VERSION 5.7 ;
  NOWIREEXTENSIONATPIN ON ;
  DIVIDERCHAR "/" ;
  BUSBITCHARS "[]" ;
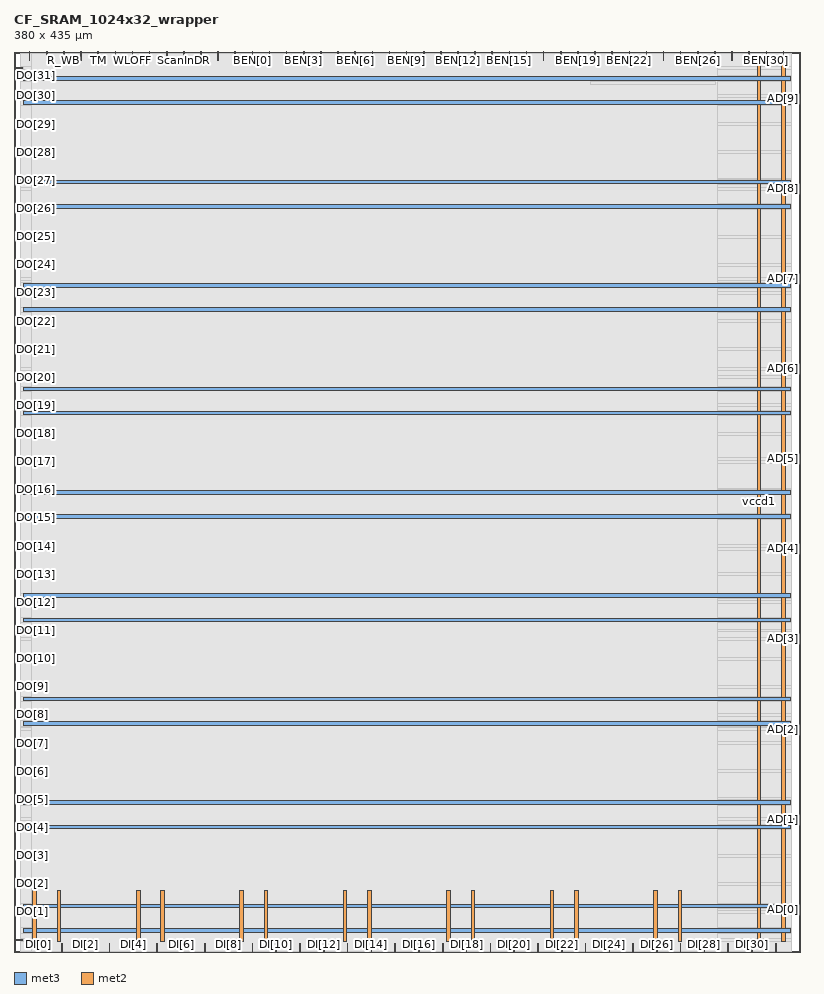
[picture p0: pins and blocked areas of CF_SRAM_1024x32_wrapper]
MACRO CF_SRAM_1024x32_wrapper
  CLASS BLOCK ;
  FOREIGN CF_SRAM_1024x32_wrapper ;
  ORIGIN 0.000 0.000 ;
  SIZE 380.000 BY 435.000 ;
  PIN AD[0]
    DIRECTION INPUT ;
    USE SIGNAL ;
    ANTENNAGATEAREA 0.247500 ;
    PORT
      LAYER met3 ;
        RECT 376.000 20.440 380.000 21.040 ;
    END
  END AD[0]
  PIN AD[1]
    DIRECTION INPUT ;
    USE SIGNAL ;
    ANTENNAGATEAREA 0.213000 ;
    PORT
      LAYER met3 ;
        RECT 376.000 63.960 380.000 64.560 ;
    END
  END AD[1]
  PIN AD[2]
    DIRECTION INPUT ;
    USE SIGNAL ;
    ANTENNAGATEAREA 0.213000 ;
    PORT
      LAYER met3 ;
        RECT 376.000 107.480 380.000 108.080 ;
    END
  END AD[2]
  PIN AD[3]
    DIRECTION INPUT ;
    USE SIGNAL ;
    ANTENNAGATEAREA 0.213000 ;
    PORT
      LAYER met3 ;
        RECT 376.000 151.000 380.000 151.600 ;
    END
  END AD[3]
  PIN AD[4]
    DIRECTION INPUT ;
    USE SIGNAL ;
    ANTENNAGATEAREA 0.159000 ;
    PORT
      LAYER met3 ;
        RECT 376.000 194.520 380.000 195.120 ;
    END
  END AD[4]
  PIN AD[5]
    DIRECTION INPUT ;
    USE SIGNAL ;
    ANTENNAGATEAREA 0.159000 ;
    PORT
      LAYER met3 ;
        RECT 376.000 238.040 380.000 238.640 ;
    END
  END AD[5]
  PIN AD[6]
    DIRECTION INPUT ;
    USE SIGNAL ;
    ANTENNAGATEAREA 0.213000 ;
    PORT
      LAYER met3 ;
        RECT 376.000 281.560 380.000 282.160 ;
    END
  END AD[6]
  PIN AD[7]
    DIRECTION INPUT ;
    USE SIGNAL ;
    ANTENNAGATEAREA 0.213000 ;
    PORT
      LAYER met3 ;
        RECT 376.000 325.080 380.000 325.680 ;
    END
  END AD[7]
  PIN AD[8]
    DIRECTION INPUT ;
    USE SIGNAL ;
    ANTENNAGATEAREA 0.213000 ;
    PORT
      LAYER met3 ;
        RECT 376.000 368.600 380.000 369.200 ;
    END
  END AD[8]
  PIN AD[9]
    DIRECTION INPUT ;
    USE SIGNAL ;
    ANTENNAGATEAREA 0.213000 ;
    PORT
      LAYER met3 ;
        RECT 376.000 412.120 380.000 412.720 ;
    END
  END AD[9]
  PIN BEN[0]
    DIRECTION INPUT ;
    USE SIGNAL ;
    ANTENNAGATEAREA 0.247500 ;
    ANTENNADIFFAREA 0.434700 ;
    PORT
      LAYER met2 ;
        RECT 115.090 431.000 115.370 435.000 ;
    END
  END BEN[0]
  PIN BEN[10]
    DIRECTION INPUT ;
    USE SIGNAL ;
    ANTENNAGATEAREA 0.247500 ;
    ANTENNADIFFAREA 0.434700 ;
    PORT
      LAYER met2 ;
        RECT 197.890 431.000 198.170 435.000 ;
    END
  END BEN[10]
  PIN BEN[11]
    DIRECTION INPUT ;
    USE SIGNAL ;
    ANTENNAGATEAREA 0.247500 ;
    ANTENNADIFFAREA 0.434700 ;
    PORT
      LAYER met2 ;
        RECT 206.170 431.000 206.450 435.000 ;
    END
  END BEN[11]
  PIN BEN[12]
    DIRECTION INPUT ;
    USE SIGNAL ;
    ANTENNAGATEAREA 0.247500 ;
    ANTENNADIFFAREA 0.434700 ;
    PORT
      LAYER met2 ;
        RECT 214.450 431.000 214.730 435.000 ;
    END
  END BEN[12]
  PIN BEN[13]
    DIRECTION INPUT ;
    USE SIGNAL ;
    ANTENNAGATEAREA 0.247500 ;
    ANTENNADIFFAREA 0.434700 ;
    PORT
      LAYER met2 ;
        RECT 222.730 431.000 223.010 435.000 ;
    END
  END BEN[13]
  PIN BEN[14]
    DIRECTION INPUT ;
    USE SIGNAL ;
    ANTENNAGATEAREA 0.247500 ;
    ANTENNADIFFAREA 0.434700 ;
    PORT
      LAYER met2 ;
        RECT 231.010 431.000 231.290 435.000 ;
    END
  END BEN[14]
  PIN BEN[15]
    DIRECTION INPUT ;
    USE SIGNAL ;
    ANTENNAGATEAREA 0.247500 ;
    ANTENNADIFFAREA 0.434700 ;
    PORT
      LAYER met2 ;
        RECT 239.290 431.000 239.570 435.000 ;
    END
  END BEN[15]
  PIN BEN[16]
    DIRECTION INPUT ;
    USE SIGNAL ;
    ANTENNAGATEAREA 0.213000 ;
    ANTENNADIFFAREA 0.434700 ;
    PORT
      LAYER met2 ;
        RECT 247.570 431.000 247.850 435.000 ;
    END
  END BEN[16]
  PIN BEN[17]
    DIRECTION INPUT ;
    USE SIGNAL ;
    ANTENNAGATEAREA 0.213000 ;
    ANTENNADIFFAREA 0.434700 ;
    PORT
      LAYER met2 ;
        RECT 255.850 431.000 256.130 435.000 ;
    END
  END BEN[17]
  PIN BEN[18]
    DIRECTION INPUT ;
    USE SIGNAL ;
    ANTENNAGATEAREA 0.159000 ;
    ANTENNADIFFAREA 0.434700 ;
    PORT
      LAYER met2 ;
        RECT 264.130 431.000 264.410 435.000 ;
    END
  END BEN[18]
  PIN BEN[19]
    DIRECTION INPUT ;
    USE SIGNAL ;
    ANTENNAGATEAREA 0.159000 ;
    ANTENNADIFFAREA 0.434700 ;
    PORT
      LAYER met2 ;
        RECT 272.410 431.000 272.690 435.000 ;
    END
  END BEN[19]
  PIN BEN[1]
    DIRECTION INPUT ;
    USE SIGNAL ;
    ANTENNAGATEAREA 0.247500 ;
    ANTENNADIFFAREA 0.434700 ;
    PORT
      LAYER met2 ;
        RECT 123.370 431.000 123.650 435.000 ;
    END
  END BEN[1]
  PIN BEN[20]
    DIRECTION INPUT ;
    USE SIGNAL ;
    ANTENNAGATEAREA 0.159000 ;
    ANTENNADIFFAREA 0.434700 ;
    PORT
      LAYER met2 ;
        RECT 280.690 431.000 280.970 435.000 ;
    END
  END BEN[20]
  PIN BEN[21]
    DIRECTION INPUT ;
    USE SIGNAL ;
    ANTENNAGATEAREA 0.159000 ;
    ANTENNADIFFAREA 0.434700 ;
    PORT
      LAYER met2 ;
        RECT 288.970 431.000 289.250 435.000 ;
    END
  END BEN[21]
  PIN BEN[22]
    DIRECTION INPUT ;
    USE SIGNAL ;
    ANTENNAGATEAREA 0.159000 ;
    ANTENNADIFFAREA 0.434700 ;
    PORT
      LAYER met2 ;
        RECT 297.250 431.000 297.530 435.000 ;
    END
  END BEN[22]
  PIN BEN[23]
    DIRECTION INPUT ;
    USE SIGNAL ;
    ANTENNAGATEAREA 0.159000 ;
    PORT
      LAYER met2 ;
        RECT 305.530 431.000 305.810 435.000 ;
    END
  END BEN[23]
  PIN BEN[24]
    DIRECTION INPUT ;
    USE SIGNAL ;
    ANTENNAGATEAREA 0.159000 ;
    PORT
      LAYER met2 ;
        RECT 313.810 431.000 314.090 435.000 ;
    END
  END BEN[24]
  PIN BEN[25]
    DIRECTION INPUT ;
    USE SIGNAL ;
    ANTENNAGATEAREA 0.159000 ;
    PORT
      LAYER met2 ;
        RECT 322.090 431.000 322.370 435.000 ;
    END
  END BEN[25]
  PIN BEN[26]
    DIRECTION INPUT ;
    USE SIGNAL ;
    ANTENNAGATEAREA 0.159000 ;
    PORT
      LAYER met2 ;
        RECT 330.370 431.000 330.650 435.000 ;
    END
  END BEN[26]
  PIN BEN[27]
    DIRECTION INPUT ;
    USE SIGNAL ;
    ANTENNAGATEAREA 0.159000 ;
    PORT
      LAYER met2 ;
        RECT 338.650 431.000 338.930 435.000 ;
    END
  END BEN[27]
  PIN BEN[28]
    DIRECTION INPUT ;
    USE SIGNAL ;
    ANTENNAGATEAREA 0.159000 ;
    PORT
      LAYER met2 ;
        RECT 346.930 431.000 347.210 435.000 ;
    END
  END BEN[28]
  PIN BEN[29]
    DIRECTION INPUT ;
    USE SIGNAL ;
    ANTENNAGATEAREA 0.159000 ;
    PORT
      LAYER met2 ;
        RECT 355.210 431.000 355.490 435.000 ;
    END
  END BEN[29]
  PIN BEN[2]
    DIRECTION INPUT ;
    USE SIGNAL ;
    ANTENNAGATEAREA 0.247500 ;
    ANTENNADIFFAREA 0.434700 ;
    PORT
      LAYER met2 ;
        RECT 131.650 431.000 131.930 435.000 ;
    END
  END BEN[2]
  PIN BEN[30]
    DIRECTION INPUT ;
    USE SIGNAL ;
    ANTENNAGATEAREA 0.159000 ;
    PORT
      LAYER met2 ;
        RECT 363.490 431.000 363.770 435.000 ;
    END
  END BEN[30]
  PIN BEN[31]
    DIRECTION INPUT ;
    USE SIGNAL ;
    ANTENNAGATEAREA 0.159000 ;
    PORT
      LAYER met2 ;
        RECT 371.770 431.000 372.050 435.000 ;
    END
  END BEN[31]
  PIN BEN[3]
    DIRECTION INPUT ;
    USE SIGNAL ;
    ANTENNAGATEAREA 0.247500 ;
    ANTENNADIFFAREA 0.434700 ;
    PORT
      LAYER met2 ;
        RECT 139.930 431.000 140.210 435.000 ;
    END
  END BEN[3]
  PIN BEN[4]
    DIRECTION INPUT ;
    USE SIGNAL ;
    ANTENNAGATEAREA 0.247500 ;
    ANTENNADIFFAREA 0.434700 ;
    PORT
      LAYER met2 ;
        RECT 148.210 431.000 148.490 435.000 ;
    END
  END BEN[4]
  PIN BEN[5]
    DIRECTION INPUT ;
    USE SIGNAL ;
    ANTENNAGATEAREA 0.247500 ;
    ANTENNADIFFAREA 0.434700 ;
    PORT
      LAYER met2 ;
        RECT 156.490 431.000 156.770 435.000 ;
    END
  END BEN[5]
  PIN BEN[6]
    DIRECTION INPUT ;
    USE SIGNAL ;
    ANTENNAGATEAREA 0.247500 ;
    ANTENNADIFFAREA 0.434700 ;
    PORT
      LAYER met2 ;
        RECT 164.770 431.000 165.050 435.000 ;
    END
  END BEN[6]
  PIN BEN[7]
    DIRECTION INPUT ;
    USE SIGNAL ;
    ANTENNAGATEAREA 0.247500 ;
    ANTENNADIFFAREA 0.434700 ;
    PORT
      LAYER met2 ;
        RECT 173.050 431.000 173.330 435.000 ;
    END
  END BEN[7]
  PIN BEN[8]
    DIRECTION INPUT ;
    USE SIGNAL ;
    ANTENNAGATEAREA 0.247500 ;
    ANTENNADIFFAREA 0.434700 ;
    PORT
      LAYER met2 ;
        RECT 181.330 431.000 181.610 435.000 ;
    END
  END BEN[8]
  PIN BEN[9]
    DIRECTION INPUT ;
    USE SIGNAL ;
    ANTENNAGATEAREA 0.247500 ;
    ANTENNADIFFAREA 0.434700 ;
    PORT
      LAYER met2 ;
        RECT 189.610 431.000 189.890 435.000 ;
    END
  END BEN[9]
  PIN CLKin
    DIRECTION INPUT ;
    USE SIGNAL ;
    PORT
      LAYER met2 ;
        RECT 7.450 431.000 7.730 435.000 ;
    END
  END CLKin
  PIN DI[0]
    DIRECTION INPUT ;
    USE SIGNAL ;
    ANTENNAGATEAREA 0.426000 ;
    PORT
      LAYER met2 ;
        RECT 11.590 0.000 11.870 4.000 ;
    END
  END DI[0]
  PIN DI[10]
    DIRECTION INPUT ;
    USE SIGNAL ;
    ANTENNAGATEAREA 0.247500 ;
    PORT
      LAYER met2 ;
        RECT 126.590 0.000 126.870 4.000 ;
    END
  END DI[10]
  PIN DI[11]
    DIRECTION INPUT ;
    USE SIGNAL ;
    ANTENNAGATEAREA 0.213000 ;
    PORT
      LAYER met2 ;
        RECT 138.090 0.000 138.370 4.000 ;
    END
  END DI[11]
  PIN DI[12]
    DIRECTION INPUT ;
    USE SIGNAL ;
    ANTENNAGATEAREA 0.213000 ;
    PORT
      LAYER met2 ;
        RECT 149.590 0.000 149.870 4.000 ;
    END
  END DI[12]
  PIN DI[13]
    DIRECTION INPUT ;
    USE SIGNAL ;
    ANTENNAGATEAREA 0.213000 ;
    PORT
      LAYER met2 ;
        RECT 161.090 0.000 161.370 4.000 ;
    END
  END DI[13]
  PIN DI[14]
    DIRECTION INPUT ;
    USE SIGNAL ;
    ANTENNAGATEAREA 0.213000 ;
    PORT
      LAYER met2 ;
        RECT 172.590 0.000 172.870 4.000 ;
    END
  END DI[14]
  PIN DI[15]
    DIRECTION INPUT ;
    USE SIGNAL ;
    ANTENNAGATEAREA 0.213000 ;
    PORT
      LAYER met2 ;
        RECT 184.090 0.000 184.370 4.000 ;
    END
  END DI[15]
  PIN DI[16]
    DIRECTION INPUT ;
    USE SIGNAL ;
    ANTENNAGATEAREA 0.247500 ;
    PORT
      LAYER met2 ;
        RECT 195.590 0.000 195.870 4.000 ;
    END
  END DI[16]
  PIN DI[17]
    DIRECTION INPUT ;
    USE SIGNAL ;
    ANTENNAGATEAREA 0.247500 ;
    PORT
      LAYER met2 ;
        RECT 207.090 0.000 207.370 4.000 ;
    END
  END DI[17]
  PIN DI[18]
    DIRECTION INPUT ;
    USE SIGNAL ;
    ANTENNAGATEAREA 0.247500 ;
    PORT
      LAYER met2 ;
        RECT 218.590 0.000 218.870 4.000 ;
    END
  END DI[18]
  PIN DI[19]
    DIRECTION INPUT ;
    USE SIGNAL ;
    ANTENNAGATEAREA 0.247500 ;
    PORT
      LAYER met2 ;
        RECT 230.090 0.000 230.370 4.000 ;
    END
  END DI[19]
  PIN DI[1]
    DIRECTION INPUT ;
    USE SIGNAL ;
    ANTENNAGATEAREA 0.247500 ;
    PORT
      LAYER met2 ;
        RECT 23.090 0.000 23.370 4.000 ;
    END
  END DI[1]
  PIN DI[20]
    DIRECTION INPUT ;
    USE SIGNAL ;
    ANTENNAGATEAREA 0.247500 ;
    PORT
      LAYER met2 ;
        RECT 241.590 0.000 241.870 4.000 ;
    END
  END DI[20]
  PIN DI[21]
    DIRECTION INPUT ;
    USE SIGNAL ;
    ANTENNAGATEAREA 0.247500 ;
    PORT
      LAYER met2 ;
        RECT 253.090 0.000 253.370 4.000 ;
    END
  END DI[21]
  PIN DI[22]
    DIRECTION INPUT ;
    USE SIGNAL ;
    ANTENNAGATEAREA 0.247500 ;
    PORT
      LAYER met2 ;
        RECT 264.590 0.000 264.870 4.000 ;
    END
  END DI[22]
  PIN DI[23]
    DIRECTION INPUT ;
    USE SIGNAL ;
    ANTENNAGATEAREA 0.247500 ;
    PORT
      LAYER met2 ;
        RECT 276.090 0.000 276.370 4.000 ;
    END
  END DI[23]
  PIN DI[24]
    DIRECTION INPUT ;
    USE SIGNAL ;
    ANTENNAGATEAREA 0.247500 ;
    PORT
      LAYER met2 ;
        RECT 287.590 0.000 287.870 4.000 ;
    END
  END DI[24]
  PIN DI[25]
    DIRECTION INPUT ;
    USE SIGNAL ;
    ANTENNAGATEAREA 0.247500 ;
    PORT
      LAYER met2 ;
        RECT 299.090 0.000 299.370 4.000 ;
    END
  END DI[25]
  PIN DI[26]
    DIRECTION INPUT ;
    USE SIGNAL ;
    ANTENNAGATEAREA 0.247500 ;
    PORT
      LAYER met2 ;
        RECT 310.590 0.000 310.870 4.000 ;
    END
  END DI[26]
  PIN DI[27]
    DIRECTION INPUT ;
    USE SIGNAL ;
    ANTENNAGATEAREA 0.247500 ;
    PORT
      LAYER met2 ;
        RECT 322.090 0.000 322.370 4.000 ;
    END
  END DI[27]
  PIN DI[28]
    DIRECTION INPUT ;
    USE SIGNAL ;
    ANTENNAGATEAREA 0.247500 ;
    PORT
      LAYER met2 ;
        RECT 333.590 0.000 333.870 4.000 ;
    END
  END DI[28]
  PIN DI[29]
    DIRECTION INPUT ;
    USE SIGNAL ;
    ANTENNAGATEAREA 0.247500 ;
    PORT
      LAYER met2 ;
        RECT 345.090 0.000 345.370 4.000 ;
    END
  END DI[29]
  PIN DI[2]
    DIRECTION INPUT ;
    USE SIGNAL ;
    ANTENNAGATEAREA 0.247500 ;
    PORT
      LAYER met2 ;
        RECT 34.590 0.000 34.870 4.000 ;
    END
  END DI[2]
  PIN DI[30]
    DIRECTION INPUT ;
    USE SIGNAL ;
    ANTENNAGATEAREA 0.247500 ;
    PORT
      LAYER met2 ;
        RECT 356.590 0.000 356.870 4.000 ;
    END
  END DI[30]
  PIN DI[31]
    DIRECTION INPUT ;
    USE SIGNAL ;
    ANTENNAGATEAREA 0.247500 ;
    PORT
      LAYER met2 ;
        RECT 368.090 0.000 368.370 4.000 ;
    END
  END DI[31]
  PIN DI[3]
    DIRECTION INPUT ;
    USE SIGNAL ;
    ANTENNAGATEAREA 0.247500 ;
    PORT
      LAYER met2 ;
        RECT 46.090 0.000 46.370 4.000 ;
    END
  END DI[3]
  PIN DI[4]
    DIRECTION INPUT ;
    USE SIGNAL ;
    ANTENNAGATEAREA 0.247500 ;
    PORT
      LAYER met2 ;
        RECT 57.590 0.000 57.870 4.000 ;
    END
  END DI[4]
  PIN DI[5]
    DIRECTION INPUT ;
    USE SIGNAL ;
    ANTENNAGATEAREA 0.247500 ;
    PORT
      LAYER met2 ;
        RECT 69.090 0.000 69.370 4.000 ;
    END
  END DI[5]
  PIN DI[6]
    DIRECTION INPUT ;
    USE SIGNAL ;
    ANTENNAGATEAREA 0.247500 ;
    PORT
      LAYER met2 ;
        RECT 80.590 0.000 80.870 4.000 ;
    END
  END DI[6]
  PIN DI[7]
    DIRECTION INPUT ;
    USE SIGNAL ;
    ANTENNAGATEAREA 0.247500 ;
    PORT
      LAYER met2 ;
        RECT 92.090 0.000 92.370 4.000 ;
    END
  END DI[7]
  PIN DI[8]
    DIRECTION INPUT ;
    USE SIGNAL ;
    ANTENNAGATEAREA 0.247500 ;
    PORT
      LAYER met2 ;
        RECT 103.590 0.000 103.870 4.000 ;
    END
  END DI[8]
  PIN DI[9]
    DIRECTION INPUT ;
    USE SIGNAL ;
    ANTENNAGATEAREA 0.247500 ;
    PORT
      LAYER met2 ;
        RECT 115.090 0.000 115.370 4.000 ;
    END
  END DI[9]
  PIN DO[0]
    DIRECTION OUTPUT TRISTATE ;
    USE SIGNAL ;
    ANTENNADIFFAREA 0.795200 ;
    PORT
      LAYER met3 ;
        RECT 0.000 5.480 4.000 6.080 ;
    END
  END DO[0]
  PIN DO[10]
    DIRECTION OUTPUT TRISTATE ;
    USE SIGNAL ;
    ANTENNADIFFAREA 0.795200 ;
    PORT
      LAYER met3 ;
        RECT 0.000 141.480 4.000 142.080 ;
    END
  END DO[10]
  PIN DO[11]
    DIRECTION OUTPUT TRISTATE ;
    USE SIGNAL ;
    ANTENNADIFFAREA 0.891000 ;
    PORT
      LAYER met3 ;
        RECT 0.000 155.080 4.000 155.680 ;
    END
  END DO[11]
  PIN DO[12]
    DIRECTION OUTPUT TRISTATE ;
    USE SIGNAL ;
    ANTENNADIFFAREA 0.891000 ;
    PORT
      LAYER met3 ;
        RECT 0.000 168.680 4.000 169.280 ;
    END
  END DO[12]
  PIN DO[13]
    DIRECTION OUTPUT TRISTATE ;
    USE SIGNAL ;
    ANTENNADIFFAREA 0.891000 ;
    PORT
      LAYER met3 ;
        RECT 0.000 182.280 4.000 182.880 ;
    END
  END DO[13]
  PIN DO[14]
    DIRECTION OUTPUT TRISTATE ;
    USE SIGNAL ;
    ANTENNADIFFAREA 0.891000 ;
    PORT
      LAYER met3 ;
        RECT 0.000 195.880 4.000 196.480 ;
    END
  END DO[14]
  PIN DO[15]
    DIRECTION OUTPUT TRISTATE ;
    USE SIGNAL ;
    ANTENNADIFFAREA 0.891000 ;
    PORT
      LAYER met3 ;
        RECT 0.000 209.480 4.000 210.080 ;
    END
  END DO[15]
  PIN DO[16]
    DIRECTION OUTPUT TRISTATE ;
    USE SIGNAL ;
    ANTENNADIFFAREA 0.891000 ;
    PORT
      LAYER met3 ;
        RECT 0.000 223.080 4.000 223.680 ;
    END
  END DO[16]
  PIN DO[17]
    DIRECTION OUTPUT TRISTATE ;
    USE SIGNAL ;
    ANTENNADIFFAREA 0.891000 ;
    PORT
      LAYER met3 ;
        RECT 0.000 236.680 4.000 237.280 ;
    END
  END DO[17]
  PIN DO[18]
    DIRECTION OUTPUT TRISTATE ;
    USE SIGNAL ;
    ANTENNADIFFAREA 0.891000 ;
    PORT
      LAYER met3 ;
        RECT 0.000 250.280 4.000 250.880 ;
    END
  END DO[18]
  PIN DO[19]
    DIRECTION OUTPUT TRISTATE ;
    USE SIGNAL ;
    ANTENNADIFFAREA 0.891000 ;
    PORT
      LAYER met3 ;
        RECT 0.000 263.880 4.000 264.480 ;
    END
  END DO[19]
  PIN DO[1]
    DIRECTION OUTPUT TRISTATE ;
    USE SIGNAL ;
    ANTENNADIFFAREA 0.795200 ;
    PORT
      LAYER met3 ;
        RECT 0.000 19.080 4.000 19.680 ;
    END
  END DO[1]
  PIN DO[20]
    DIRECTION OUTPUT TRISTATE ;
    USE SIGNAL ;
    ANTENNADIFFAREA 0.891000 ;
    PORT
      LAYER met3 ;
        RECT 0.000 277.480 4.000 278.080 ;
    END
  END DO[20]
  PIN DO[21]
    DIRECTION OUTPUT TRISTATE ;
    USE SIGNAL ;
    ANTENNADIFFAREA 0.891000 ;
    PORT
      LAYER met3 ;
        RECT 0.000 291.080 4.000 291.680 ;
    END
  END DO[21]
  PIN DO[22]
    DIRECTION OUTPUT TRISTATE ;
    USE SIGNAL ;
    ANTENNADIFFAREA 0.891000 ;
    PORT
      LAYER met3 ;
        RECT 0.000 304.680 4.000 305.280 ;
    END
  END DO[22]
  PIN DO[23]
    DIRECTION OUTPUT TRISTATE ;
    USE SIGNAL ;
    ANTENNADIFFAREA 0.891000 ;
    PORT
      LAYER met3 ;
        RECT 0.000 318.280 4.000 318.880 ;
    END
  END DO[23]
  PIN DO[24]
    DIRECTION OUTPUT TRISTATE ;
    USE SIGNAL ;
    ANTENNADIFFAREA 0.891000 ;
    PORT
      LAYER met3 ;
        RECT 0.000 331.880 4.000 332.480 ;
    END
  END DO[24]
  PIN DO[25]
    DIRECTION OUTPUT TRISTATE ;
    USE SIGNAL ;
    ANTENNADIFFAREA 0.891000 ;
    PORT
      LAYER met3 ;
        RECT 0.000 345.480 4.000 346.080 ;
    END
  END DO[25]
  PIN DO[26]
    DIRECTION OUTPUT TRISTATE ;
    USE SIGNAL ;
    ANTENNADIFFAREA 0.891000 ;
    PORT
      LAYER met3 ;
        RECT 0.000 359.080 4.000 359.680 ;
    END
  END DO[26]
  PIN DO[27]
    DIRECTION OUTPUT TRISTATE ;
    USE SIGNAL ;
    ANTENNADIFFAREA 0.891000 ;
    PORT
      LAYER met3 ;
        RECT 0.000 372.680 4.000 373.280 ;
    END
  END DO[27]
  PIN DO[28]
    DIRECTION OUTPUT TRISTATE ;
    USE SIGNAL ;
    ANTENNADIFFAREA 0.891000 ;
    PORT
      LAYER met3 ;
        RECT 0.000 386.280 4.000 386.880 ;
    END
  END DO[28]
  PIN DO[29]
    DIRECTION OUTPUT TRISTATE ;
    USE SIGNAL ;
    ANTENNADIFFAREA 1.590400 ;
    PORT
      LAYER met3 ;
        RECT 0.000 399.880 4.000 400.480 ;
    END
  END DO[29]
  PIN DO[2]
    DIRECTION OUTPUT TRISTATE ;
    USE SIGNAL ;
    ANTENNADIFFAREA 0.795200 ;
    PORT
      LAYER met3 ;
        RECT 0.000 32.680 4.000 33.280 ;
    END
  END DO[2]
  PIN DO[30]
    DIRECTION OUTPUT TRISTATE ;
    USE SIGNAL ;
    ANTENNADIFFAREA 1.590400 ;
    PORT
      LAYER met3 ;
        RECT 0.000 413.480 4.000 414.080 ;
    END
  END DO[30]
  PIN DO[31]
    DIRECTION OUTPUT TRISTATE ;
    USE SIGNAL ;
    ANTENNADIFFAREA 1.590400 ;
    PORT
      LAYER met3 ;
        RECT 0.000 427.080 4.000 427.680 ;
    END
  END DO[31]
  PIN DO[3]
    DIRECTION OUTPUT TRISTATE ;
    USE SIGNAL ;
    ANTENNADIFFAREA 0.795200 ;
    PORT
      LAYER met3 ;
        RECT 0.000 46.280 4.000 46.880 ;
    END
  END DO[3]
  PIN DO[4]
    DIRECTION OUTPUT TRISTATE ;
    USE SIGNAL ;
    ANTENNADIFFAREA 0.795200 ;
    PORT
      LAYER met3 ;
        RECT 0.000 59.880 4.000 60.480 ;
    END
  END DO[4]
  PIN DO[5]
    DIRECTION OUTPUT TRISTATE ;
    USE SIGNAL ;
    ANTENNADIFFAREA 0.795200 ;
    PORT
      LAYER met3 ;
        RECT 0.000 73.480 4.000 74.080 ;
    END
  END DO[5]
  PIN DO[6]
    DIRECTION OUTPUT TRISTATE ;
    USE SIGNAL ;
    ANTENNADIFFAREA 0.795200 ;
    PORT
      LAYER met3 ;
        RECT 0.000 87.080 4.000 87.680 ;
    END
  END DO[6]
  PIN DO[7]
    DIRECTION OUTPUT TRISTATE ;
    USE SIGNAL ;
    ANTENNADIFFAREA 0.795200 ;
    PORT
      LAYER met3 ;
        RECT 0.000 100.680 4.000 101.280 ;
    END
  END DO[7]
  PIN DO[8]
    DIRECTION OUTPUT TRISTATE ;
    USE SIGNAL ;
    ANTENNADIFFAREA 0.795200 ;
    PORT
      LAYER met3 ;
        RECT 0.000 114.280 4.000 114.880 ;
    END
  END DO[8]
  PIN DO[9]
    DIRECTION OUTPUT TRISTATE ;
    USE SIGNAL ;
    ANTENNADIFFAREA 0.795200 ;
    PORT
      LAYER met3 ;
        RECT 0.000 127.880 4.000 128.480 ;
    END
  END DO[9]
  PIN EN
    DIRECTION INPUT ;
    USE SIGNAL ;
    ANTENNAGATEAREA 0.247500 ;
    ANTENNADIFFAREA 1.738800 ;
    PORT
      LAYER met2 ;
        RECT 15.730 431.000 16.010 435.000 ;
    END
  END EN
  PIN R_WB
    DIRECTION INPUT ;
    USE SIGNAL ;
    ANTENNAGATEAREA 0.247500 ;
    ANTENNADIFFAREA 0.434700 ;
    PORT
      LAYER met2 ;
        RECT 24.010 431.000 24.290 435.000 ;
    END
  END R_WB
  PIN SM
    DIRECTION INPUT ;
    USE SIGNAL ;
    ANTENNAGATEAREA 0.247500 ;
    ANTENNADIFFAREA 0.434700 ;
    PORT
      LAYER met2 ;
        RECT 32.290 431.000 32.570 435.000 ;
    END
  END SM
  PIN ScanInCC
    DIRECTION INPUT ;
    USE SIGNAL ;
    ANTENNAGATEAREA 0.247500 ;
    ANTENNADIFFAREA 0.434700 ;
    PORT
      LAYER met2 ;
        RECT 65.410 431.000 65.690 435.000 ;
    END
  END ScanInCC
  PIN ScanInDL
    DIRECTION INPUT ;
    USE SIGNAL ;
    ANTENNAGATEAREA 0.247500 ;
    ANTENNADIFFAREA 0.434700 ;
    PORT
      LAYER met2 ;
        RECT 73.690 431.000 73.970 435.000 ;
    END
  END ScanInDL
  PIN ScanInDR
    DIRECTION INPUT ;
    USE SIGNAL ;
    ANTENNAGATEAREA 0.159000 ;
    ANTENNADIFFAREA 1.304100 ;
    PORT
      LAYER met2 ;
        RECT 81.970 431.000 82.250 435.000 ;
    END
  END ScanInDR
  PIN ScanOutCC
    DIRECTION OUTPUT TRISTATE ;
    USE SIGNAL ;
    ANTENNADIFFAREA 0.891000 ;
    PORT
      LAYER met2 ;
        RECT 90.250 431.000 90.530 435.000 ;
    END
  END ScanOutCC
  PIN TM
    DIRECTION INPUT ;
    USE SIGNAL ;
    ANTENNAGATEAREA 0.247500 ;
    ANTENNADIFFAREA 0.434700 ;
    PORT
      LAYER met2 ;
        RECT 40.570 431.000 40.850 435.000 ;
    END
  END TM
  PIN WLBI
    DIRECTION INPUT ;
    USE SIGNAL ;
    ANTENNAGATEAREA 0.213000 ;
    ANTENNADIFFAREA 0.434700 ;
    PORT
      LAYER met2 ;
        RECT 48.850 431.000 49.130 435.000 ;
    END
  END WLBI
  PIN WLOFF
    DIRECTION INPUT ;
    USE SIGNAL ;
    ANTENNAGATEAREA 0.247500 ;
    ANTENNADIFFAREA 0.434700 ;
    PORT
      LAYER met2 ;
        RECT 57.130 431.000 57.410 435.000 ;
    END
  END WLOFF
  PIN vccd1
    DIRECTION INOUT ;
    USE POWER ;
    PORT
      LAYER met2 ;
        RECT 9.180 5.200 10.940 29.720 ;
    END
    PORT
      LAYER met2 ;
        RECT 59.180 5.200 60.940 29.720 ;
    END
    PORT
      LAYER met2 ;
        RECT 109.180 5.200 110.940 29.720 ;
    END
    PORT
      LAYER met2 ;
        RECT 159.180 5.200 160.940 29.720 ;
    END
    PORT
      LAYER met2 ;
        RECT 209.180 5.200 210.940 29.720 ;
    END
    PORT
      LAYER met2 ;
        RECT 259.180 5.200 260.940 29.720 ;
    END
    PORT
      LAYER met2 ;
        RECT 309.180 5.200 310.940 29.720 ;
    END
    PORT
      LAYER met2 ;
        RECT 359.180 5.200 360.940 430.000 ;
    END
    PORT
      LAYER met3 ;
        RECT 4.820 9.560 375.140 11.320 ;
    END
    PORT
      LAYER met3 ;
        RECT 4.820 59.560 375.140 61.320 ;
    END
    PORT
      LAYER met3 ;
        RECT 4.820 109.560 375.140 111.320 ;
    END
    PORT
      LAYER met3 ;
        RECT 4.820 159.560 375.140 161.320 ;
    END
    PORT
      LAYER met3 ;
        RECT 4.820 209.560 375.140 211.320 ;
    END
    PORT
      LAYER met3 ;
        RECT 4.820 259.560 375.140 261.320 ;
    END
    PORT
      LAYER met3 ;
        RECT 4.820 309.560 375.140 311.320 ;
    END
    PORT
      LAYER met3 ;
        RECT 4.820 359.560 375.140 361.320 ;
    END
    PORT
      LAYER met3 ;
        RECT 4.820 409.560 375.140 411.320 ;
    END
  END vccd1
  PIN vpwrac
    DIRECTION INPUT ;
    USE SIGNAL ;
    ANTENNAGATEAREA 0.495000 ;
    ANTENNADIFFAREA 0.434700 ;
    PORT
      LAYER met2 ;
        RECT 98.530 431.000 98.810 435.000 ;
    END
  END vpwrac
  PIN vpwrpc
    DIRECTION INPUT ;
    USE SIGNAL ;
    ANTENNAGATEAREA 0.495000 ;
    ANTENNADIFFAREA 0.434700 ;
    PORT
      LAYER met2 ;
        RECT 106.810 431.000 107.090 435.000 ;
    END
  END vpwrpc
  PIN vssd1
    DIRECTION INOUT ;
    USE GROUND ;
    PORT
      LAYER met2 ;
        RECT 20.940 5.200 22.700 29.720 ;
    END
    PORT
      LAYER met2 ;
        RECT 70.940 5.200 72.700 29.720 ;
    END
    PORT
      LAYER met2 ;
        RECT 120.940 5.200 122.700 29.720 ;
    END
    PORT
      LAYER met2 ;
        RECT 170.940 5.200 172.700 29.720 ;
    END
    PORT
      LAYER met2 ;
        RECT 220.940 5.200 222.700 29.720 ;
    END
    PORT
      LAYER met2 ;
        RECT 270.940 5.200 272.700 29.720 ;
    END
    PORT
      LAYER met2 ;
        RECT 320.940 5.200 322.700 29.720 ;
    END
    PORT
      LAYER met2 ;
        RECT 370.940 5.200 372.700 430.000 ;
    END
    PORT
      LAYER met3 ;
        RECT 4.820 21.320 375.140 23.080 ;
    END
    PORT
      LAYER met3 ;
        RECT 4.820 71.320 375.140 73.080 ;
    END
    PORT
      LAYER met3 ;
        RECT 4.820 121.320 375.140 123.080 ;
    END
    PORT
      LAYER met3 ;
        RECT 4.820 171.320 375.140 173.080 ;
    END
    PORT
      LAYER met3 ;
        RECT 4.820 221.320 375.140 223.080 ;
    END
    PORT
      LAYER met3 ;
        RECT 4.820 271.320 375.140 273.080 ;
    END
    PORT
      LAYER met3 ;
        RECT 4.820 321.320 375.140 323.080 ;
    END
    PORT
      LAYER met3 ;
        RECT 4.820 371.320 375.140 373.080 ;
    END
    PORT
      LAYER met3 ;
        RECT 4.820 421.320 375.140 423.080 ;
    END
  END vssd1
  OBS
      LAYER li1 ;
        RECT 5.060 5.355 374.900 429.845 ;
      LAYER met1 ;
        RECT 5.060 2.760 375.290 430.400 ;
      LAYER met2 ;
        RECT 6.530 430.720 7.170 434.365 ;
        RECT 8.010 430.720 15.450 434.365 ;
        RECT 16.290 430.720 23.730 434.365 ;
        RECT 24.570 430.720 32.010 434.365 ;
        RECT 32.850 430.720 40.290 434.365 ;
        RECT 41.130 430.720 48.570 434.365 ;
        RECT 49.410 430.720 56.850 434.365 ;
        RECT 57.690 430.720 65.130 434.365 ;
        RECT 65.970 430.720 73.410 434.365 ;
        RECT 74.250 430.720 81.690 434.365 ;
        RECT 82.530 430.720 89.970 434.365 ;
        RECT 90.810 430.720 98.250 434.365 ;
        RECT 99.090 430.720 106.530 434.365 ;
        RECT 107.370 430.720 114.810 434.365 ;
        RECT 115.650 430.720 123.090 434.365 ;
        RECT 123.930 430.720 131.370 434.365 ;
        RECT 132.210 430.720 139.650 434.365 ;
        RECT 140.490 430.720 147.930 434.365 ;
        RECT 148.770 430.720 156.210 434.365 ;
        RECT 157.050 430.720 164.490 434.365 ;
        RECT 165.330 430.720 172.770 434.365 ;
        RECT 173.610 430.720 181.050 434.365 ;
        RECT 181.890 430.720 189.330 434.365 ;
        RECT 190.170 430.720 197.610 434.365 ;
        RECT 198.450 430.720 205.890 434.365 ;
        RECT 206.730 430.720 214.170 434.365 ;
        RECT 215.010 430.720 222.450 434.365 ;
        RECT 223.290 430.720 230.730 434.365 ;
        RECT 231.570 430.720 239.010 434.365 ;
        RECT 239.850 430.720 247.290 434.365 ;
        RECT 248.130 430.720 255.570 434.365 ;
        RECT 256.410 430.720 263.850 434.365 ;
        RECT 264.690 430.720 272.130 434.365 ;
        RECT 272.970 430.720 280.410 434.365 ;
        RECT 281.250 430.720 288.690 434.365 ;
        RECT 289.530 430.720 296.970 434.365 ;
        RECT 297.810 430.720 305.250 434.365 ;
        RECT 306.090 430.720 313.530 434.365 ;
        RECT 314.370 430.720 321.810 434.365 ;
        RECT 322.650 430.720 330.090 434.365 ;
        RECT 330.930 430.720 338.370 434.365 ;
        RECT 339.210 430.720 346.650 434.365 ;
        RECT 347.490 430.720 354.930 434.365 ;
        RECT 355.770 430.720 363.210 434.365 ;
        RECT 364.050 430.720 371.490 434.365 ;
        RECT 372.330 430.720 375.260 434.365 ;
        RECT 6.530 430.280 375.260 430.720 ;
        RECT 6.530 30.000 358.900 430.280 ;
        RECT 6.530 4.920 8.900 30.000 ;
        RECT 11.220 4.920 20.660 30.000 ;
        RECT 22.980 4.920 58.900 30.000 ;
        RECT 61.220 4.920 70.660 30.000 ;
        RECT 72.980 4.920 108.900 30.000 ;
        RECT 111.220 4.920 120.660 30.000 ;
        RECT 122.980 4.920 158.900 30.000 ;
        RECT 161.220 4.920 170.660 30.000 ;
        RECT 172.980 4.920 208.900 30.000 ;
        RECT 211.220 4.920 220.660 30.000 ;
        RECT 222.980 4.920 258.900 30.000 ;
        RECT 261.220 4.920 270.660 30.000 ;
        RECT 272.980 4.920 308.900 30.000 ;
        RECT 311.220 4.920 320.660 30.000 ;
        RECT 322.980 4.920 358.900 30.000 ;
        RECT 361.220 4.920 370.660 430.280 ;
        RECT 372.980 4.920 375.260 430.280 ;
        RECT 6.530 4.280 375.260 4.920 ;
        RECT 6.530 0.155 11.310 4.280 ;
        RECT 12.150 0.155 22.810 4.280 ;
        RECT 23.650 0.155 34.310 4.280 ;
        RECT 35.150 0.155 45.810 4.280 ;
        RECT 46.650 0.155 57.310 4.280 ;
        RECT 58.150 0.155 68.810 4.280 ;
        RECT 69.650 0.155 80.310 4.280 ;
        RECT 81.150 0.155 91.810 4.280 ;
        RECT 92.650 0.155 103.310 4.280 ;
        RECT 104.150 0.155 114.810 4.280 ;
        RECT 115.650 0.155 126.310 4.280 ;
        RECT 127.150 0.155 137.810 4.280 ;
        RECT 138.650 0.155 149.310 4.280 ;
        RECT 150.150 0.155 160.810 4.280 ;
        RECT 161.650 0.155 172.310 4.280 ;
        RECT 173.150 0.155 183.810 4.280 ;
        RECT 184.650 0.155 195.310 4.280 ;
        RECT 196.150 0.155 206.810 4.280 ;
        RECT 207.650 0.155 218.310 4.280 ;
        RECT 219.150 0.155 229.810 4.280 ;
        RECT 230.650 0.155 241.310 4.280 ;
        RECT 242.150 0.155 252.810 4.280 ;
        RECT 253.650 0.155 264.310 4.280 ;
        RECT 265.150 0.155 275.810 4.280 ;
        RECT 276.650 0.155 287.310 4.280 ;
        RECT 288.150 0.155 298.810 4.280 ;
        RECT 299.650 0.155 310.310 4.280 ;
        RECT 311.150 0.155 321.810 4.280 ;
        RECT 322.650 0.155 333.310 4.280 ;
        RECT 334.150 0.155 344.810 4.280 ;
        RECT 345.650 0.155 356.310 4.280 ;
        RECT 357.150 0.155 367.810 4.280 ;
        RECT 368.650 0.155 375.260 4.280 ;
      LAYER met3 ;
        RECT 3.070 428.080 376.000 434.345 ;
        RECT 4.400 426.680 376.000 428.080 ;
        RECT 3.070 423.480 376.000 426.680 ;
        RECT 3.070 420.920 4.420 423.480 ;
        RECT 375.540 420.920 376.000 423.480 ;
        RECT 3.070 414.480 376.000 420.920 ;
        RECT 4.400 413.120 376.000 414.480 ;
        RECT 4.400 413.080 375.600 413.120 ;
        RECT 3.070 411.720 375.600 413.080 ;
        RECT 3.070 409.160 4.420 411.720 ;
        RECT 375.540 409.160 376.000 411.720 ;
        RECT 3.070 400.880 376.000 409.160 ;
        RECT 4.400 399.480 376.000 400.880 ;
        RECT 3.070 387.280 376.000 399.480 ;
        RECT 4.400 385.880 376.000 387.280 ;
        RECT 3.070 373.680 376.000 385.880 ;
        RECT 4.400 373.480 376.000 373.680 ;
        RECT 4.400 372.280 4.420 373.480 ;
        RECT 3.070 370.920 4.420 372.280 ;
        RECT 375.540 370.920 376.000 373.480 ;
        RECT 3.070 369.600 376.000 370.920 ;
        RECT 3.070 368.200 375.600 369.600 ;
        RECT 3.070 361.720 376.000 368.200 ;
        RECT 3.070 360.080 4.420 361.720 ;
        RECT 4.400 359.160 4.420 360.080 ;
        RECT 375.540 359.160 376.000 361.720 ;
        RECT 4.400 358.680 376.000 359.160 ;
        RECT 3.070 346.480 376.000 358.680 ;
        RECT 4.400 345.080 376.000 346.480 ;
        RECT 3.070 332.880 376.000 345.080 ;
        RECT 4.400 331.480 376.000 332.880 ;
        RECT 3.070 326.080 376.000 331.480 ;
        RECT 3.070 324.680 375.600 326.080 ;
        RECT 3.070 323.480 376.000 324.680 ;
        RECT 3.070 320.920 4.420 323.480 ;
        RECT 375.540 320.920 376.000 323.480 ;
        RECT 3.070 319.280 376.000 320.920 ;
        RECT 4.400 317.880 376.000 319.280 ;
        RECT 3.070 311.720 376.000 317.880 ;
        RECT 3.070 309.160 4.420 311.720 ;
        RECT 375.540 309.160 376.000 311.720 ;
        RECT 3.070 305.680 376.000 309.160 ;
        RECT 4.400 304.280 376.000 305.680 ;
        RECT 3.070 292.080 376.000 304.280 ;
        RECT 4.400 290.680 376.000 292.080 ;
        RECT 3.070 282.560 376.000 290.680 ;
        RECT 3.070 281.160 375.600 282.560 ;
        RECT 3.070 278.480 376.000 281.160 ;
        RECT 4.400 277.080 376.000 278.480 ;
        RECT 3.070 273.480 376.000 277.080 ;
        RECT 3.070 270.920 4.420 273.480 ;
        RECT 375.540 270.920 376.000 273.480 ;
        RECT 3.070 264.880 376.000 270.920 ;
        RECT 4.400 263.480 376.000 264.880 ;
        RECT 3.070 261.720 376.000 263.480 ;
        RECT 3.070 259.160 4.420 261.720 ;
        RECT 375.540 259.160 376.000 261.720 ;
        RECT 3.070 251.280 376.000 259.160 ;
        RECT 4.400 249.880 376.000 251.280 ;
        RECT 3.070 239.040 376.000 249.880 ;
        RECT 3.070 237.680 375.600 239.040 ;
        RECT 4.400 237.640 375.600 237.680 ;
        RECT 4.400 236.280 376.000 237.640 ;
        RECT 3.070 224.080 376.000 236.280 ;
        RECT 4.400 223.480 376.000 224.080 ;
        RECT 4.400 222.680 4.420 223.480 ;
        RECT 3.070 220.920 4.420 222.680 ;
        RECT 375.540 220.920 376.000 223.480 ;
        RECT 3.070 211.720 376.000 220.920 ;
        RECT 3.070 210.480 4.420 211.720 ;
        RECT 4.400 209.160 4.420 210.480 ;
        RECT 375.540 209.160 376.000 211.720 ;
        RECT 4.400 209.080 376.000 209.160 ;
        RECT 3.070 196.880 376.000 209.080 ;
        RECT 4.400 195.520 376.000 196.880 ;
        RECT 4.400 195.480 375.600 195.520 ;
        RECT 3.070 194.120 375.600 195.480 ;
        RECT 3.070 183.280 376.000 194.120 ;
        RECT 4.400 181.880 376.000 183.280 ;
        RECT 3.070 173.480 376.000 181.880 ;
        RECT 3.070 170.920 4.420 173.480 ;
        RECT 375.540 170.920 376.000 173.480 ;
        RECT 3.070 169.680 376.000 170.920 ;
        RECT 4.400 168.280 376.000 169.680 ;
        RECT 3.070 161.720 376.000 168.280 ;
        RECT 3.070 159.160 4.420 161.720 ;
        RECT 375.540 159.160 376.000 161.720 ;
        RECT 3.070 156.080 376.000 159.160 ;
        RECT 4.400 154.680 376.000 156.080 ;
        RECT 3.070 152.000 376.000 154.680 ;
        RECT 3.070 150.600 375.600 152.000 ;
        RECT 3.070 142.480 376.000 150.600 ;
        RECT 4.400 141.080 376.000 142.480 ;
        RECT 3.070 128.880 376.000 141.080 ;
        RECT 4.400 127.480 376.000 128.880 ;
        RECT 3.070 123.480 376.000 127.480 ;
        RECT 3.070 120.920 4.420 123.480 ;
        RECT 375.540 120.920 376.000 123.480 ;
        RECT 3.070 115.280 376.000 120.920 ;
        RECT 4.400 113.880 376.000 115.280 ;
        RECT 3.070 111.720 376.000 113.880 ;
        RECT 3.070 109.160 4.420 111.720 ;
        RECT 375.540 109.160 376.000 111.720 ;
        RECT 3.070 108.480 376.000 109.160 ;
        RECT 3.070 107.080 375.600 108.480 ;
        RECT 3.070 101.680 376.000 107.080 ;
        RECT 4.400 100.280 376.000 101.680 ;
        RECT 3.070 88.080 376.000 100.280 ;
        RECT 4.400 86.680 376.000 88.080 ;
        RECT 3.070 74.480 376.000 86.680 ;
        RECT 4.400 73.480 376.000 74.480 ;
        RECT 4.400 73.080 4.420 73.480 ;
        RECT 3.070 70.920 4.420 73.080 ;
        RECT 375.540 70.920 376.000 73.480 ;
        RECT 3.070 64.960 376.000 70.920 ;
        RECT 3.070 63.560 375.600 64.960 ;
        RECT 3.070 61.720 376.000 63.560 ;
        RECT 3.070 60.880 4.420 61.720 ;
        RECT 4.400 59.480 4.420 60.880 ;
        RECT 3.070 59.160 4.420 59.480 ;
        RECT 375.540 59.160 376.000 61.720 ;
        RECT 3.070 47.280 376.000 59.160 ;
        RECT 4.400 45.880 376.000 47.280 ;
        RECT 3.070 33.680 376.000 45.880 ;
        RECT 4.400 32.280 376.000 33.680 ;
        RECT 3.070 23.480 376.000 32.280 ;
        RECT 3.070 20.920 4.420 23.480 ;
        RECT 375.540 21.440 376.000 23.480 ;
        RECT 375.540 20.920 375.600 21.440 ;
        RECT 3.070 20.080 375.600 20.920 ;
        RECT 4.400 20.040 375.600 20.080 ;
        RECT 4.400 18.680 376.000 20.040 ;
        RECT 3.070 11.720 376.000 18.680 ;
        RECT 3.070 9.160 4.420 11.720 ;
        RECT 375.540 9.160 376.000 11.720 ;
        RECT 3.070 6.480 376.000 9.160 ;
        RECT 4.400 5.080 376.000 6.480 ;
        RECT 3.070 0.175 376.000 5.080 ;
      LAYER met4 ;
        RECT 8.575 0.175 340.105 434.345 ;
      LAYER met5 ;
        RECT 278.420 419.100 338.900 420.700 ;
  END
END CF_SRAM_1024x32_wrapper
END LIBRARY

